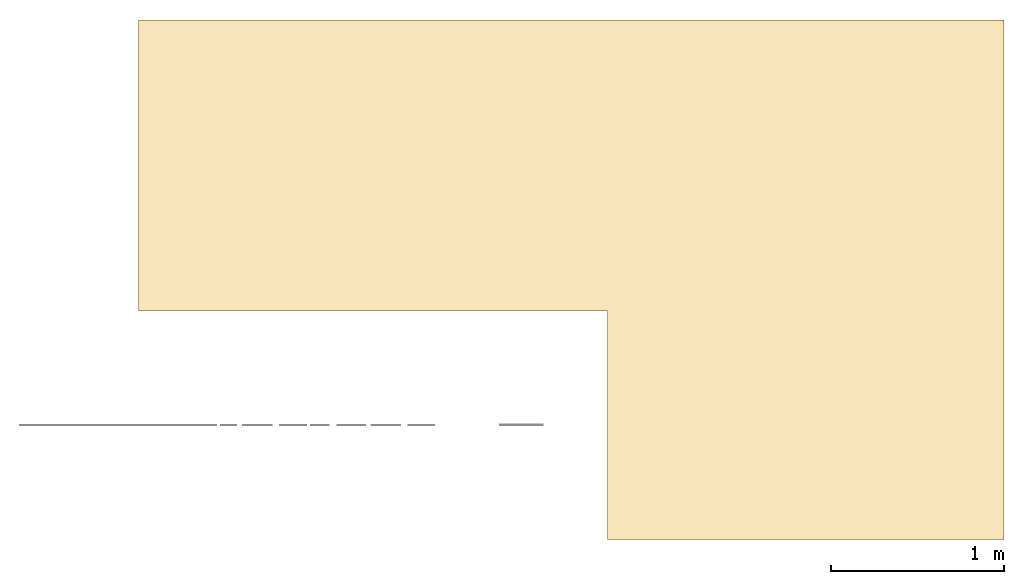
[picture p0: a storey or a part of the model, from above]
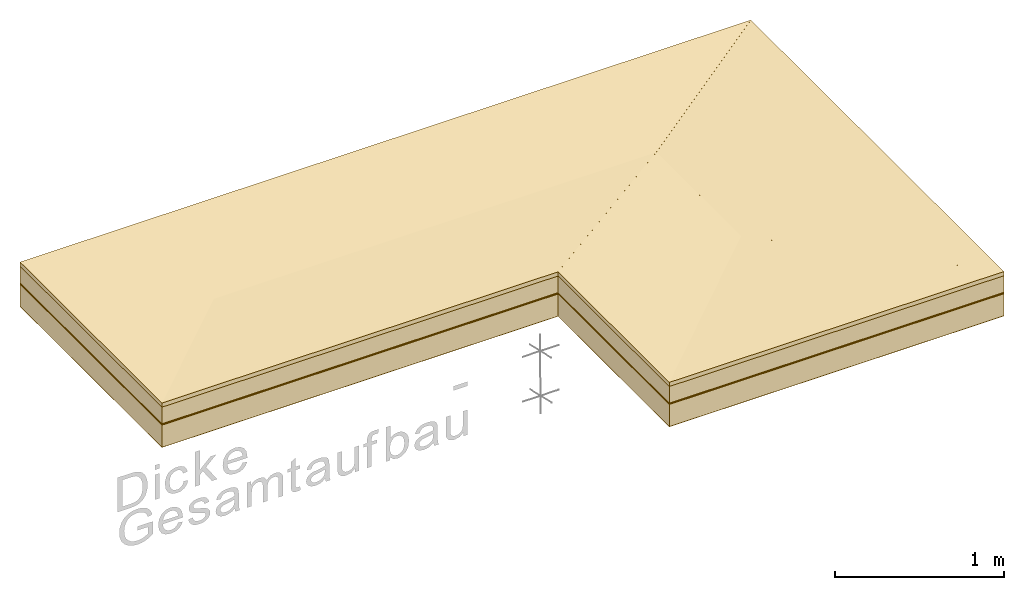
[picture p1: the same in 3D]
Properties of the parts of a building model (IFC4)

# File
Description: no view
File name: ÖBV_OEBV_Richtlinie_Flachdachaufbau.ifc
Time: 2024-03-13T09:46:47
Author: Oesterreichische Bautechnik Vereinigung
Organization: OEBV
Written by: ODA SDAI 24.5
Authorization: OEBV

# IfcSite, Liegenschaft
RefLatitude: 48, 8, 10, 320000; RefLongitude: 11, 41, 19, 320000

# IfcBuildingStorey (2)
In: Gebäude
Elevation: 0 m
Name
Geschoss 01
Geschoss 02

# IfcSpace, FD 03
In: Geschoss 02
LongName: Flachdach
AllplanAttributes - Allright_Bauteil_ID: 0066Rau0000000032

# IfcBuildingElementProxy (2)
In: Geschoss 02
Name | Allright_Bauteil_ID
macro | 0066Mak0000000017
macro | 0066Mak0000000022

# IfcCovering (6)
In: FD 03
Description: Bodenschicht; PredefinedType: FLOORING
Name | Material | Allright_Bauteil_ID
FD 03 | Dampfsperre 0.002 m | 0066Bfl0000000025/01
FD 03 | Wärmedämmung 0.16 m | 0066Bfl0000000025/02
FD 03 | Abdichtung 2-lagig 0.005 m | 0066Bfl0000000025/03
FD 03 | Struktur-/Speichervlies 0.005 m | 0066Bfl0000000025/04
FD 03 | Substrat/Schubsicherung 0.12 m | 0066Bfl0000000025/05
FD 03 | Vegetationsmatte 0.03 m | 0066Bfl0000000025/06

# IfcElementAssembly (3)
Name | In | Allright_Bauteil_ID
SpatialDim_Group | Geschoss 02 | 0066Elg0000000018
SpatialDim_Group | Geschoss 02 | 0066Elg0000000023
FD 03 | FD 03 | Description: Bodenschicht

# IfcSlab
In: Geschoss 01
PredefinedType: FLOOR
AllplanAttributes - Allright_Bauteil_ID: 0016De 0000004953
